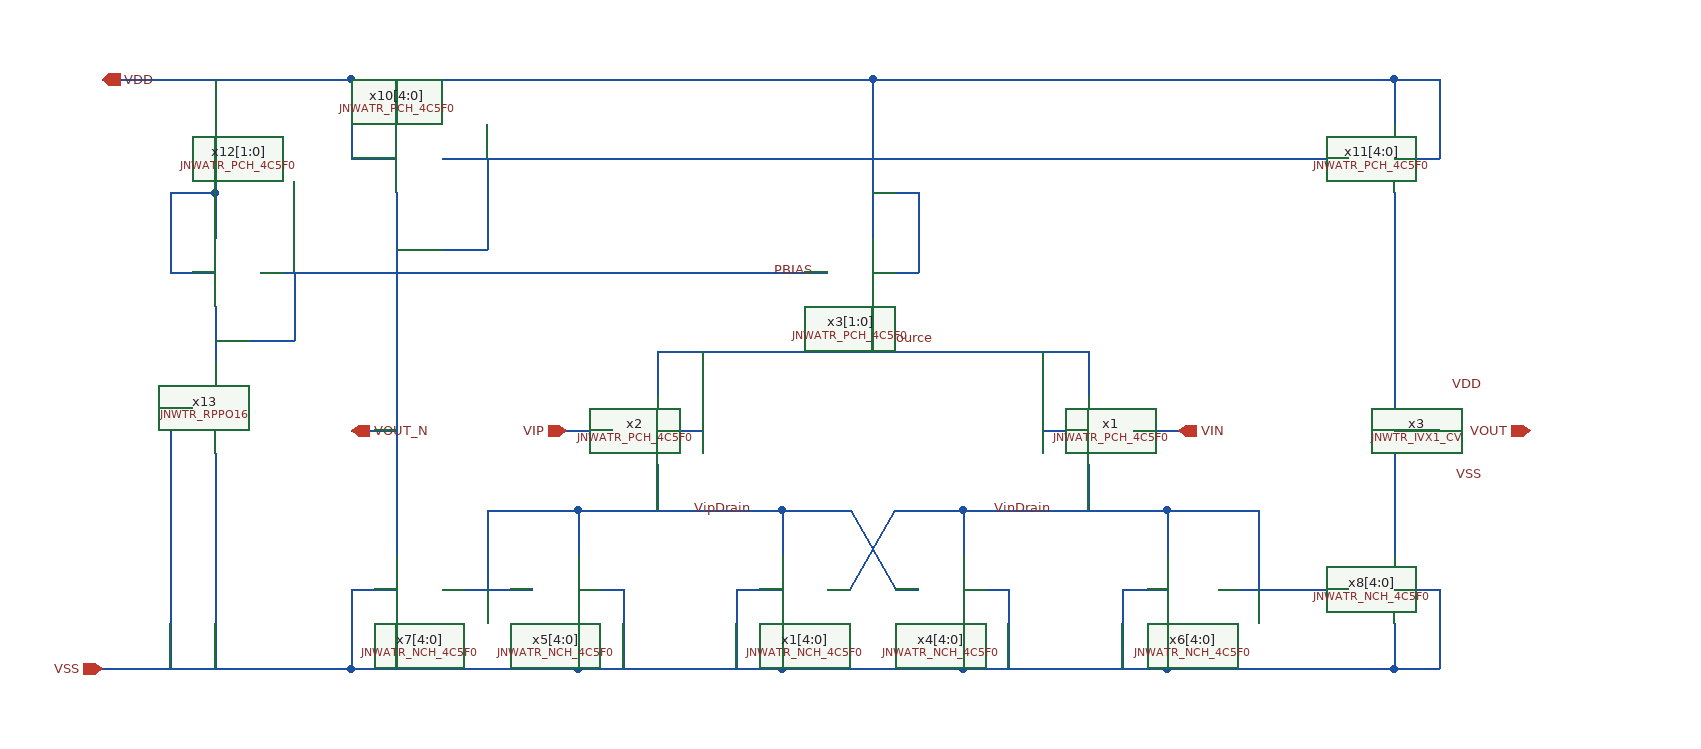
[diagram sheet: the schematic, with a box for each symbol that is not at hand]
v {xschem version=3.4.6 file_version=1.2}
G {}
K {}
V {}
S {}
E {}
N 1240 -550 1240 -510 {
lab=VipDrain}
N 1420 -550 1420 -510 {
lab=VipDrain}
N 1580 -550 1580 -510 {
lab=VinDrain}
N 1680 -550 1760 -550 {
lab=VinDrain}
N 1460 -480 1480 -480 {
lab=VinDrain}
N 1480 -480 1520 -550 {
lab=VinDrain}
N 1520 -480 1540 -480 {
lab=VipDrain}
N 1480 -550 1520 -480 {
lab=VipDrain}
N 1420 -550 1480 -550 {
lab=VipDrain}
N 1520 -550 1580 -550 {
lab=VinDrain}
N 1160 -550 1240 -550 {
lab=VipDrain}
N 1160 -550 1160 -480 {
lab=VipDrain}
N 1160 -860 1160 -780 {
lab=VOUT_N}
N 1730 -930 1960 -930 {
lab=VDD}
N 1880 -410 1960 -410 {
lab=VSS}
N 1310 -690 1310 -650 {
lab=inSource}
N 1690 -690 1690 -650 {
lab=inSource}
N 1230 -620 1270 -620 {lab=VIP}
N 1730 -620 1770 -620 {lab=VIN}
N 1580 -550 1680 -550 {
lab=VinDrain}
N 1240 -550 1420 -550 {
lab=VipDrain}
N 960 -760 1460 -760 {lab=PBIAS}
N 1500 -730 1500 -690 {lab=inSource}
N 1310 -690 1690 -690 {
lab=inSource}
N 1120 -860 1920 -860 {
lab=VOUT_N}
N 1080 -780 1160 -780 {
lab=VOUT_N}
N 1040 -930 1500 -930 {
lab=VDD}
N 1500 -930 1500 -790 {lab=VDD}
N 1080 -930 1080 -890 {lab=VDD}
N 820 -930 1040 -930 {
lab=VDD}
N 1960 -620 2000 -620 {lab=#net1}
N 1040 -480 1040 -410 {lab=VSS}
N 820 -410 1040 -410 {
lab=VSS}
N 1040 -410 1120 -410 {
lab=VSS}
N 1120 -410 1240 -410 {
lab=VSS}
N 1240 -450 1240 -410 {lab=VSS}
N 1420 -450 1420 -410 {lab=VSS}
N 1240 -410 1420 -410 {
lab=VSS}
N 1420 -410 1580 -410 {
lab=VSS}
N 1760 -450 1760 -410 {lab=VSS}
N 1580 -410 1760 -410 {
lab=VSS}
N 1760 -410 1880 -410 {
lab=VSS}
N 1960 -450 1960 -410 {lab=VSS}
N 1500 -930 1730 -930 {
lab=VDD}
N 1960 -860 2000 -860 {lab=VDD}
N 1960 -930 1960 -890 {lab=VDD}
N 1960 -930 2000 -930 {lab=VDD}
N 1040 -930 1040 -860 {lab=VDD}
N 1040 -860 1080 -860 {lab=VDD}
N 2000 -930 2000 -860 {lab=VDD}
N 1500 -760 1540 -760 {lab=VDD}
N 1540 -830 1540 -760 {lab=VDD}
N 1500 -830 1540 -830 {lab=VDD}
N 1240 -480 1280 -480 {lab=VSS}
N 1280 -480 1280 -410 {lab=VSS}
N 1380 -480 1380 -410 {lab=VSS}
N 1380 -480 1420 -480 {lab=VSS}
N 1620 -480 1620 -410 {lab=VSS}
N 1580 -480 1620 -480 {lab=VSS}
N 1760 -550 1760 -510 {lab=VinDrain}
N 1720 -480 1760 -480 {lab=VSS}
N 1720 -480 1720 -410 {lab=VSS}
N 1805 -480 1920 -480 {lab=VinDrain}
N 1120 -480 1200 -480 {lab=VipDrain}
N 1760 -550 1840 -550 {lab=VinDrain}
N 1840 -550 1840 -480 {lab=VinDrain}
N 1310 -590 1310 -550 {lab=VipDrain}
N 1690 -590 1690 -550 {lab=VinDrain}
N 1040 -480 1080 -480 {lab=VSS}
N 1080 -450 1080 -410 {lab=VSS}
N 1310 -620 1350 -620 {lab=inSource}
N 1650 -620 1690 -620 {lab=inSource}
N 1960 -830 1960 -510 {lab=#net1}
N 1080 -830 1080 -510 {lab=VOUT_N}
N 1960 -480 2000 -480 {lab=VSS}
N 2000 -480 2000 -410 {lab=VSS}
N 1960 -410 2000 -410 {lab=VSS}
N 1580 -450 1580 -410 {lab=VSS}
N 880 -640 900 -640 {lab=VSS}
N 920 -730 920 -680 {lab=PBIAS}
N 880 -760 920 -760 {lab=VDD}
N 880 -830 880 -760 {lab=VDD}
N 880 -830 920 -830 {lab=VDD}
N 920 -830 920 -790 {lab=VDD}
N 920 -700 990 -700 {lab=PBIAS}
N 990 -760 990 -700 {lab=PBIAS}
N 1040 -620 1080 -620 {lab=VOUT_N}
N 920 -600 920 -410 {lab=VSS}
N 1650 -690 1650 -620 {lab=inSource}
N 1350 -690 1350 -620 {lab=inSource}
N 920 -930 920 -830 {lab=VDD}
N 880 -640 880 -410 {lab=VSS}
C {devices/ipin.sym} 820 -410 0 0 {name=p2 lab=VSS
}
C {devices/ipin.sym} 820 -930 2 1 {name=p3 lab=VDD
}
C {JNW_ATR_SKY130A/JNWATR_PCH_4C5F0.sym} 1920 -860 0 0 {name=x11[4:0]}
C {JNW_ATR_SKY130A/JNWATR_PCH_4C5F0.sym} 1120 -860 0 1 {name=x10[4:0]}
C {devices/opin.sym} 2080 -620 2 1 {name=p7 lab=VOUT}
C {devices/lab_wire.sym} 1660 -550 0 0 {name=p12 sig_type=std_logic lab=VinDrain}
C {devices/lab_wire.sym} 1340 -550 0 1 {name=p13 sig_type=std_logic lab=VipDrain}
C {devices/lab_wire.sym} 1500 -700 0 1 {name=p47 sig_type=std_logic lab=inSource}
C {devices/lab_wire.sym} 1450 -760 0 0 {name=p23 sig_type=std_logic lab=PBIAS}
C {JNW_ATR_SKY130A/JNWATR_PCH_4C5F0.sym} 1460 -760 0 0 {name=x3[1:0]}
C {JNW_ATR_SKY130A/JNWATR_PCH_4C5F0.sym} 1730 -620 0 1 {name=x1}
C {devices/ipin.sym} 1230 -620 0 0 {name=p9 lab=VIP}
C {devices/ipin.sym} 1770 -620 0 1 {name=p14 lab=VIN}
C {devices/opin.sym} 1040 -620 2 0 {name=p10 lab=VOUT_N}
C {JNW_ATR_SKY130A/JNWATR_PCH_4C5F0.sym} 1270 -620 0 0 {name=x2}
C {JNW_ATR_SKY130A/JNWATR_PCH_4C5F0.sym} 960 -760 0 1 {name=x12[1:0]}
C {JNW_TR_SKY130A/JNWTR_RPPO16.sym} 920 -680 1 0 {name=x13 }
C {JNW_ATR_SKY130A/JNWATR_NCH_4C5F0.sym} 1460 -480 0 1 {name=x1[4:0]}
C {JNW_ATR_SKY130A/JNWATR_NCH_4C5F0.sym} 1540 -480 0 0 {name=x4[4:0]}
C {JNW_ATR_SKY130A/JNWATR_NCH_4C5F0.sym} 1200 -480 0 0 {name=x5[4:0]}
C {JNW_ATR_SKY130A/JNWATR_NCH_4C5F0.sym} 1800 -480 0 1 {name=x6[4:0]}
C {JNW_ATR_SKY130A/JNWATR_NCH_4C5F0.sym} 1120 -480 0 1 {name=x7[4:0]}
C {JNW_ATR_SKY130A/JNWATR_NCH_4C5F0.sym} 1920 -480 0 0 {name=x8[4:0]}
C {devices/lab_wire.sym} 2040 -660 0 0 {name=p1 sig_type=std_logic lab=VDD}
C {devices/lab_wire.sym} 2040 -580 2 1 {name=p4 sig_type=std_logic lab=VSS}
C {JNW_TR_SKY130A/JNWTR_IVX1_CV.sym} 2000 -620 0 0 {name=x3 }
